! (c) 2009  Infineon Technologies AG, Munich
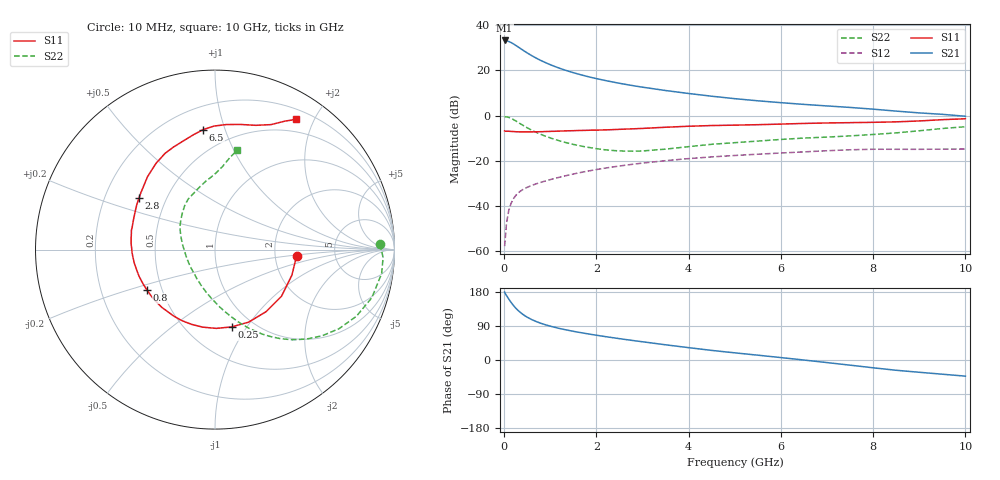
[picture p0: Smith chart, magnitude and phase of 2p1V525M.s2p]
! Infineon Technologies  Discrete & RF Semiconductors
! BFP420
! VCE =  1.5 V,  IC =  25 mA
! Common Emitter S-Parameters:  Nov 2009
# GHz  S  MA  R  50
!  f  S11  S21  S12  S22
! GHz  MAG  ANG  MAG  ANG  MAG  ANG  MAG  ANG
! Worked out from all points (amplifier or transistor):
!   46 points, 10 MHz to 10 GHz, reference 50 ohm
!   highest |S21| = 33.2 dB at 10 MHz (marker M1)
!   |S21| within 3 dB of that: start of sweep to 312.9 MHz
!   unconditionally stable (mu >= 1): 1.604 GHz to end of sweep
!   at 300 MHz: K = 0.37, MSG = 32.3 dB, |S12| = -34.2 dB
!   at 1.7 GHz: K = 1.02, MAG = 20.6 dB, |S12| = -25.0 dB
!   at 10 GHz: K = 1.06, MAG = 5.7 dB, |S12| = -14.8 dB
!   lowest NFmin = 1.38 dB at 900 MHz
!   S11 on the Smith chart (normalised r, x): 10 MHz: 2.67, -0.24; 250 MHz: 0.80, -0.85; 800 MHz: 0.41, -0.23; 2.8 GHz: 0.35, +0.27; 6.5 GHz: 0.35, +0.85; 10 GHz: 0.33, +1.75
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0.01  0.4595 -4.5  45.93 179.4  0.0013 102.7  0.9201 1.9
0.02  0.453 -7.2  45.12 176.3  0.0017 91.3  0.9375 -2.7
0.05  0.4515 -18.4  44.84 170.4  0.0041 84.7  0.938 -8.2
0.1  0.4525 -35.1  43.6 160.9  0.008 78.4  0.9138 -17.1
0.15  0.4477 -50.7  41.33 152.0  0.0115 73.4  0.8711 -25.2
0.2  0.4455 -65.2  38.71 144.2  0.0145 68.9  0.8198 -32.5
0.25  0.4405 -77.9  35.81 137.1  0.0171 65.4  0.7663 -38.8
0.35  0.4374 -98.9  30.66 125.7  0.0213 60.2  0.6626 -49.3
0.4  0.4366 -107.3  28.34 120.9  0.023 58.6  0.6169 -53.6
0.5  0.436 -121.5  24.34 113.0  0.026 56.3  0.538 -60.9
0.6  0.4377 -132.7  21.15 106.5  0.0287 55.0  0.4751 -66.9
0.8  0.4413 -149.3  16.5 96.7  0.0336 54.1  0.3837 -76.6
1  0.4488 -161.2  13.38 89.3  0.0385 53.9  0.3215 -85.2
1.2  0.4559 -170.4  11.18 83.2  0.0435 53.7  0.2771 -93.2
1.7  0.4717 172.5  7.826 71.4  0.0564 52.0  0.2097 -112.8
2.8  0.5113 146.0  4.59 51.3  0.0844 44.4  0.1639 -160.3
3.5  0.5539 132.7  3.591 40.1  0.101 38.1  0.1817 172.2
5.5  0.6306 106.3  2.128 12.7  0.1403 19.6  0.2737 131.6
6.5  0.6723 95.6  1.772 -0.1  0.1581 10.3  0.3193 117.8
7  0.6883 90.4  1.638 -6.8  0.1674 5.4  0.3354 110.8
8.5  0.7289 71.8  1.259 -27.1  0.1803 -11.8  0.4156 90.9
10  0.8534 58.2  0.969 -42.6  0.1828 -22.9  0.5681 77.3
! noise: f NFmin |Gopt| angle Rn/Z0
0.9  1.38  0.22  -154  0.13
1.8  1.65  0.29  -143  0.13
2.4  1.81  0.26  -138  0.17
3  1.83  0.34  -129  0.18
4  1.97  0.45  -112  0.27
5  2.4  0.49  -95  0.44
6  2.85  0.54  -84  0.65
